VERSION 5.7 ;
  NOWIREEXTENSIONATPIN ON ;
  DIVIDERCHAR "/" ;
  BUSBITCHARS "[]" ;
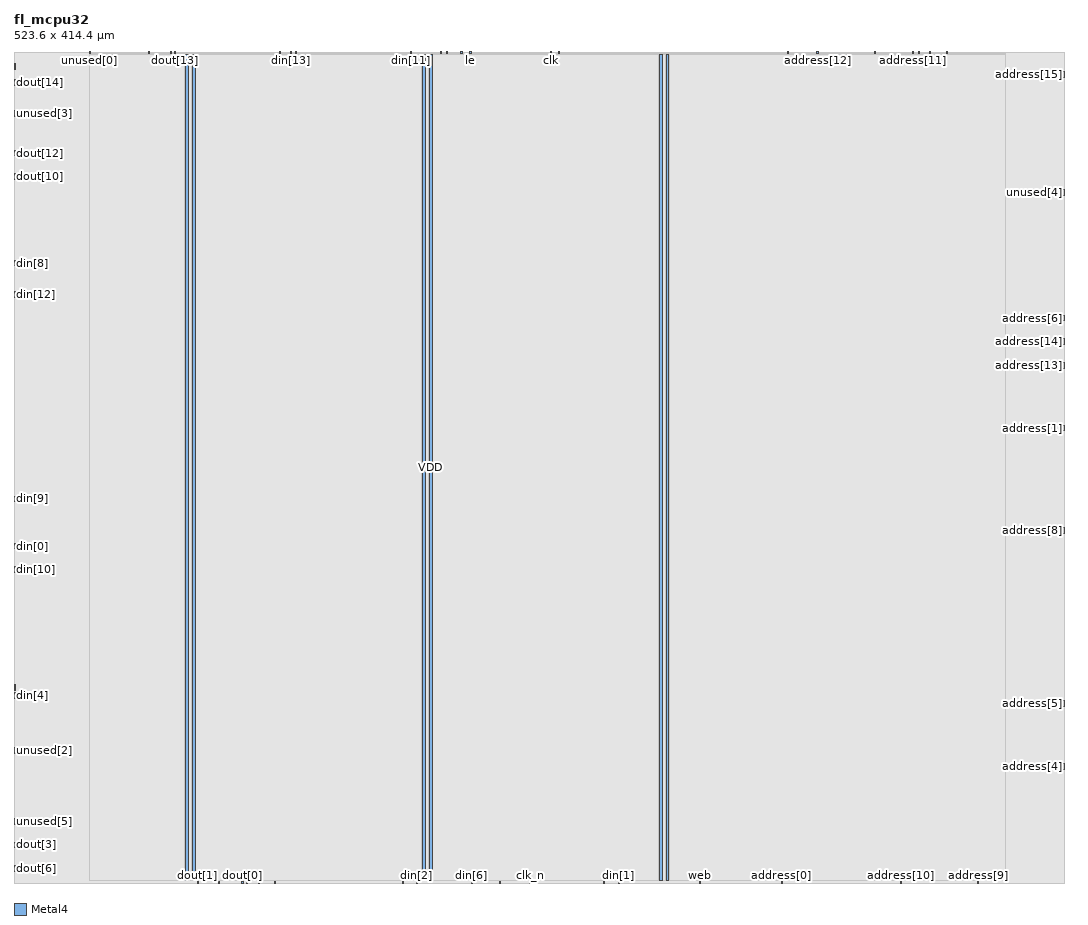
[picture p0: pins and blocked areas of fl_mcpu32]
MACRO fl_mcpu32
  CLASS BLOCK ;
  FOREIGN fl_mcpu32 ;
  ORIGIN 0.000 0.000 ;
  SIZE 523.600 BY 414.400 ;
  PIN VSS
    DIRECTION INOUT ;
    USE GROUND ;
    PORT
      LAYER Metal4 ;
        RECT 85.540 1.400 86.940 413.000 ;
    END
    PORT
      LAYER Metal4 ;
        RECT 203.700 1.400 205.100 413.000 ;
    END
    PORT
      LAYER Metal4 ;
        RECT 321.860 1.400 323.260 413.000 ;
    END
  END VSS
  PIN VDD
    DIRECTION INOUT ;
    USE POWER ;
    PORT
      LAYER Metal4 ;
        RECT 88.900 1.400 90.300 413.000 ;
    END
    PORT
      LAYER Metal4 ;
        RECT 207.060 1.400 208.460 413.000 ;
    END
    PORT
      LAYER Metal4 ;
        RECT 325.220 1.400 326.620 413.000 ;
    END
  END VDD
  PIN le
    DIRECTION OUTPUT ;
    USE SIGNAL ;
    ANTENNADIFFAREA 8.338300 ;
    PORT
      LAYER Metal4 ;
        RECT 227.360 413.840 227.920 414.400 ;
    END
  END le
  PIN clk
    DIRECTION INPUT ;
    USE SIGNAL ;
    ANTENNAGATEAREA 2.352000 ;
    ANTENNADIFFAREA 0.877000 ;
    PORT
      LAYER Metal4 ;
        RECT 267.680 413.840 268.240 414.400 ;
    END
  END clk
  PIN rst_n
    DIRECTION INPUT ;
    USE SIGNAL ;
    ANTENNAGATEAREA 1.999200 ;
    ANTENNADIFFAREA 0.877000 ;
    PORT
      LAYER Metal4 ;
        RECT 212.800 413.840 213.360 414.400 ;
    END
  END rst_n
  PIN rst_override_n
    DIRECTION INPUT ;
    USE SIGNAL ;
    ANTENNAGATEAREA 1.999200 ;
    ANTENNADIFFAREA 0.877000 ;
    PORT
      LAYER Metal4 ;
        RECT 77.840 413.840 78.400 414.400 ;
    END
  END rst_override_n
  PIN din[0]
    DIRECTION INPUT ;
    USE SIGNAL ;
    ANTENNAGATEAREA 1.999200 ;
    ANTENNADIFFAREA 0.877000 ;
    PORT
      LAYER Metal4 ;
        RECT 0.000 166.600 0.560 169.400 ;
    END
  END din[0]
  PIN clk_n
    DIRECTION INPUT ;
    USE SIGNAL ;
    ANTENNAGATEAREA 2.352000 ;
    ANTENNADIFFAREA 0.877000 ;
    PORT
      LAYER Metal4 ;
        RECT 257.040 0.000 257.600 0.560 ;
    END
  END clk_n
  PIN din[11]
    DIRECTION INPUT ;
    USE SIGNAL ;
    ANTENNAGATEAREA 1.999200 ;
    ANTENNADIFFAREA 0.877000 ;
    PORT
      LAYER Metal4 ;
        RECT 197.680 413.840 198.240 414.400 ;
    END
  END din[11]
  PIN din[10]
    DIRECTION INPUT ;
    USE SIGNAL ;
    ANTENNAGATEAREA 1.999200 ;
    ANTENNADIFFAREA 0.877000 ;
    PORT
      LAYER Metal4 ;
        RECT 0.000 154.840 0.560 157.640 ;
    END
  END din[10]
  PIN din[9]
    DIRECTION INPUT ;
    USE SIGNAL ;
    ANTENNAGATEAREA 1.999200 ;
    ANTENNADIFFAREA 0.877000 ;
    PORT
      LAYER Metal4 ;
        RECT 0.000 190.120 0.560 192.920 ;
    END
  END din[9]
  PIN din[8]
    DIRECTION INPUT ;
    USE SIGNAL ;
    ANTENNAGATEAREA 1.999200 ;
    ANTENNADIFFAREA 0.877000 ;
    PORT
      LAYER Metal4 ;
        RECT 0.000 307.720 0.560 310.520 ;
    END
  END din[8]
  PIN din[7]
    DIRECTION INPUT ;
    USE SIGNAL ;
    ANTENNAGATEAREA 1.999200 ;
    ANTENNADIFFAREA 0.877000 ;
    PORT
      LAYER Metal4 ;
        RECT 122.080 0.000 122.640 0.560 ;
    END
  END din[7]
  PIN din[6]
    DIRECTION INPUT ;
    USE SIGNAL ;
    ANTENNAGATEAREA 1.999200 ;
    ANTENNADIFFAREA 0.877000 ;
    PORT
      LAYER Metal4 ;
        RECT 227.920 0.000 228.480 0.560 ;
    END
  END din[6]
  PIN din[5]
    DIRECTION INPUT ;
    USE SIGNAL ;
    ANTENNAGATEAREA 1.999200 ;
    ANTENNADIFFAREA 0.877000 ;
    PORT
      LAYER Metal4 ;
        RECT 129.920 0.000 130.480 0.560 ;
    END
  END din[5]
  PIN din[4]
    DIRECTION INPUT ;
    USE SIGNAL ;
    ANTENNAGATEAREA 1.999200 ;
    ANTENNADIFFAREA 0.877000 ;
    PORT
      LAYER Metal4 ;
        RECT 0.000 92.120 0.560 94.920 ;
    END
  END din[4]
  PIN din[3]
    DIRECTION INPUT ;
    USE SIGNAL ;
    ANTENNAGATEAREA 1.999200 ;
    ANTENNADIFFAREA 0.877000 ;
    PORT
      LAYER Metal4 ;
        RECT 193.760 0.000 194.320 0.560 ;
    END
  END din[3]
  PIN din[2]
    DIRECTION INPUT ;
    USE SIGNAL ;
    ANTENNAGATEAREA 1.999200 ;
    ANTENNADIFFAREA 0.877000 ;
    PORT
      LAYER Metal4 ;
        RECT 200.480 0.000 201.040 0.560 ;
    END
  END din[2]
  PIN din[1]
    DIRECTION INPUT ;
    USE SIGNAL ;
    ANTENNAGATEAREA 1.999200 ;
    ANTENNADIFFAREA 0.877000 ;
    PORT
      LAYER Metal4 ;
        RECT 301.280 0.000 301.840 0.560 ;
    END
  END din[1]
  PIN din[12]
    DIRECTION INPUT ;
    USE SIGNAL ;
    ANTENNAGATEAREA 1.999200 ;
    ANTENNADIFFAREA 0.877000 ;
    PORT
      LAYER Metal4 ;
        RECT 0.000 292.040 0.560 294.840 ;
    END
  END din[12]
  PIN din[13]
    DIRECTION INPUT ;
    USE SIGNAL ;
    ANTENNAGATEAREA 1.999200 ;
    ANTENNADIFFAREA 0.877000 ;
    PORT
      LAYER Metal4 ;
        RECT 137.760 413.840 138.320 414.400 ;
    END
  END din[13]
  PIN din[15]
    DIRECTION INPUT ;
    USE SIGNAL ;
    ANTENNAGATEAREA 1.999200 ;
    ANTENNADIFFAREA 0.877000 ;
    PORT
      LAYER Metal4 ;
        RECT 241.920 0.000 242.480 0.560 ;
    END
  END din[15]
  PIN din[14]
    DIRECTION INPUT ;
    USE SIGNAL ;
    ANTENNAGATEAREA 1.999200 ;
    ANTENNADIFFAREA 0.877000 ;
    PORT
      LAYER Metal4 ;
        RECT 140.560 413.840 141.120 414.400 ;
    END
  END din[14]
  PIN address[0]
    DIRECTION OUTPUT ;
    USE SIGNAL ;
    ANTENNADIFFAREA 8.338300 ;
    PORT
      LAYER Metal4 ;
        RECT 382.480 0.000 383.040 0.560 ;
    END
  END address[0]
  PIN address[1]
    DIRECTION OUTPUT ;
    USE SIGNAL ;
    ANTENNADIFFAREA 8.338300 ;
    PORT
      LAYER Metal4 ;
        RECT 523.040 225.400 523.600 228.200 ;
    END
  END address[1]
  PIN address[11]
    DIRECTION OUTPUT ;
    USE SIGNAL ;
    ANTENNADIFFAREA 8.338300 ;
    PORT
      LAYER Metal4 ;
        RECT 448.000 413.840 448.560 414.400 ;
    END
  END address[11]
  PIN address[7]
    DIRECTION OUTPUT ;
    USE SIGNAL ;
    ANTENNADIFFAREA 8.338300 ;
    PORT
      LAYER Metal4 ;
        RECT 456.400 413.840 456.960 414.400 ;
    END
  END address[7]
  PIN address[8]
    DIRECTION OUTPUT ;
    USE SIGNAL ;
    ANTENNADIFFAREA 8.338300 ;
    PORT
      LAYER Metal4 ;
        RECT 523.040 174.440 523.600 177.240 ;
    END
  END address[8]
  PIN address[6]
    DIRECTION OUTPUT ;
    USE SIGNAL ;
    ANTENNADIFFAREA 8.338300 ;
    PORT
      LAYER Metal4 ;
        RECT 523.040 280.280 523.600 283.080 ;
    END
  END address[6]
  PIN address[4]
    DIRECTION OUTPUT ;
    USE SIGNAL ;
    ANTENNADIFFAREA 8.338300 ;
    PORT
      LAYER Metal4 ;
        RECT 523.040 56.840 523.600 59.640 ;
    END
  END address[4]
  PIN address[3]
    DIRECTION OUTPUT ;
    USE SIGNAL ;
    ANTENNADIFFAREA 8.338300 ;
    PORT
      LAYER Metal4 ;
        RECT 464.800 413.840 465.360 414.400 ;
    END
  END address[3]
  PIN address[13]
    DIRECTION OUTPUT ;
    USE SIGNAL ;
    ANTENNADIFFAREA 8.338300 ;
    PORT
      LAYER Metal4 ;
        RECT 523.040 256.760 523.600 259.560 ;
    END
  END address[13]
  PIN address[14]
    DIRECTION OUTPUT ;
    USE SIGNAL ;
    ANTENNADIFFAREA 8.338300 ;
    PORT
      LAYER Metal4 ;
        RECT 523.040 268.520 523.600 271.320 ;
    END
  END address[14]
  PIN address[12]
    DIRECTION OUTPUT ;
    USE SIGNAL ;
    ANTENNADIFFAREA 8.338300 ;
    PORT
      LAYER Metal4 ;
        RECT 400.400 413.840 400.960 414.400 ;
    END
  END address[12]
  PIN address[9]
    DIRECTION OUTPUT ;
    USE SIGNAL ;
    ANTENNADIFFAREA 8.338300 ;
    PORT
      LAYER Metal4 ;
        RECT 480.480 0.000 481.040 0.560 ;
    END
  END address[9]
  PIN address[2]
    DIRECTION OUTPUT ;
    USE SIGNAL ;
    ANTENNADIFFAREA 8.338300 ;
    PORT
      LAYER Metal4 ;
        RECT 450.800 413.840 451.360 414.400 ;
    END
  END address[2]
  PIN address[15]
    DIRECTION OUTPUT ;
    USE SIGNAL ;
    ANTENNADIFFAREA 8.338300 ;
    PORT
      LAYER Metal4 ;
        RECT 523.040 401.800 523.600 404.600 ;
    END
  END address[15]
  PIN address[10]
    DIRECTION OUTPUT ;
    USE SIGNAL ;
    ANTENNADIFFAREA 8.338300 ;
    PORT
      LAYER Metal4 ;
        RECT 441.840 0.000 442.400 0.560 ;
    END
  END address[10]
  PIN address[5]
    DIRECTION OUTPUT ;
    USE SIGNAL ;
    ANTENNADIFFAREA 8.338300 ;
    PORT
      LAYER Metal4 ;
        RECT 523.040 88.200 523.600 91.000 ;
    END
  END address[5]
  PIN dout[1]
    DIRECTION OUTPUT ;
    USE SIGNAL ;
    ANTENNADIFFAREA 8.338300 ;
    PORT
      LAYER Metal4 ;
        RECT 91.280 0.000 91.840 0.560 ;
    END
  END dout[1]
  PIN dout[2]
    DIRECTION OUTPUT ;
    USE SIGNAL ;
    ANTENNADIFFAREA 8.338300 ;
    PORT
      LAYER Metal4 ;
        RECT 294.000 0.000 294.560 0.560 ;
    END
  END dout[2]
  PIN dout[3]
    DIRECTION OUTPUT ;
    USE SIGNAL ;
    ANTENNADIFFAREA 8.338300 ;
    PORT
      LAYER Metal4 ;
        RECT 0.000 17.640 0.560 20.440 ;
    END
  END dout[3]
  PIN dout[4]
    DIRECTION OUTPUT ;
    USE SIGNAL ;
    ANTENNADIFFAREA 8.338300 ;
    PORT
      LAYER Metal4 ;
        RECT 215.600 413.840 216.160 414.400 ;
    END
  END dout[4]
  PIN dout[5]
    DIRECTION OUTPUT ;
    USE SIGNAL ;
    ANTENNADIFFAREA 8.338300 ;
    PORT
      LAYER Metal4 ;
        RECT 222.880 413.840 223.440 414.400 ;
    END
  END dout[5]
  PIN dout[6]
    DIRECTION OUTPUT ;
    USE SIGNAL ;
    ANTENNADIFFAREA 8.338300 ;
    PORT
      LAYER Metal4 ;
        RECT 0.000 5.880 0.560 8.680 ;
    END
  END dout[6]
  PIN dout[7]
    DIRECTION OUTPUT ;
    USE SIGNAL ;
    ANTENNADIFFAREA 8.338300 ;
    PORT
      LAYER Metal4 ;
        RECT 115.920 0.000 116.480 0.560 ;
    END
  END dout[7]
  PIN dout[15]
    DIRECTION OUTPUT ;
    USE SIGNAL ;
    ANTENNADIFFAREA 8.338300 ;
    PORT
      LAYER Metal4 ;
        RECT 0.000 405.720 0.560 408.520 ;
    END
  END dout[15]
  PIN dout[14]
    DIRECTION OUTPUT ;
    USE SIGNAL ;
    ANTENNADIFFAREA 8.338300 ;
    PORT
      LAYER Metal4 ;
        RECT 0.000 397.880 0.560 400.680 ;
    END
  END dout[14]
  PIN dout[13]
    DIRECTION OUTPUT ;
    USE SIGNAL ;
    ANTENNADIFFAREA 8.338300 ;
    PORT
      LAYER Metal4 ;
        RECT 80.080 413.840 80.640 414.400 ;
    END
  END dout[13]
  PIN dout[12]
    DIRECTION OUTPUT ;
    USE SIGNAL ;
    ANTENNADIFFAREA 8.338300 ;
    PORT
      LAYER Metal4 ;
        RECT 0.000 362.600 0.560 365.400 ;
    END
  END dout[12]
  PIN dout[11]
    DIRECTION OUTPUT ;
    USE SIGNAL ;
    ANTENNADIFFAREA 8.338300 ;
    PORT
      LAYER Metal4 ;
        RECT 101.920 0.000 102.480 0.560 ;
    END
  END dout[11]
  PIN dout[10]
    DIRECTION OUTPUT ;
    USE SIGNAL ;
    ANTENNADIFFAREA 8.338300 ;
    PORT
      LAYER Metal4 ;
        RECT 0.000 350.840 0.560 353.640 ;
    END
  END dout[10]
  PIN dout[9]
    DIRECTION OUTPUT ;
    USE SIGNAL ;
    ANTENNADIFFAREA 8.338300 ;
    PORT
      LAYER Metal4 ;
        RECT 132.160 413.840 132.720 414.400 ;
    END
  END dout[9]
  PIN dout[8]
    DIRECTION OUTPUT ;
    USE SIGNAL ;
    ANTENNADIFFAREA 8.338300 ;
    PORT
      LAYER Metal4 ;
        RECT 67.200 413.840 67.760 414.400 ;
    END
  END dout[8]
  PIN dout[0]
    DIRECTION OUTPUT ;
    USE SIGNAL ;
    ANTENNADIFFAREA 8.338300 ;
    PORT
      LAYER Metal4 ;
        RECT 113.680 0.000 114.240 0.560 ;
    END
  END dout[0]
  PIN oeb
    DIRECTION OUTPUT ;
    USE SIGNAL ;
    ANTENNADIFFAREA 8.338300 ;
    PORT
      LAYER Metal4 ;
        RECT 271.600 413.840 272.160 414.400 ;
    END
  END oeb
  PIN bus_enable
    DIRECTION OUTPUT ;
    USE SIGNAL ;
    ANTENNADIFFAREA 8.338300 ;
    PORT
      LAYER Metal4 ;
        RECT 385.840 413.840 386.400 414.400 ;
    END
  END bus_enable
  PIN web
    DIRECTION OUTPUT ;
    USE SIGNAL ;
    ANTENNADIFFAREA 8.338300 ;
    PORT
      LAYER Metal4 ;
        RECT 341.600 0.000 342.160 0.560 ;
    END
  END web
  PIN unused[0]
    DIRECTION OUTPUT ;
    USE SIGNAL ;
    ANTENNADIFFAREA 8.338300 ;
    PORT
      LAYER Metal4 ;
        RECT 37.520 413.840 38.080 414.400 ;
    END
  END unused[0]
  PIN unused[1]
    DIRECTION OUTPUT ;
    USE SIGNAL ;
    ANTENNADIFFAREA 8.338300 ;
    PORT
      LAYER Metal4 ;
        RECT 428.960 413.840 429.520 414.400 ;
    END
  END unused[1]
  PIN unused[2]
    DIRECTION OUTPUT ;
    USE SIGNAL ;
    ANTENNADIFFAREA 8.338300 ;
    PORT
      LAYER Metal4 ;
        RECT 0.000 64.680 0.560 67.480 ;
    END
  END unused[2]
  PIN unused[3]
    DIRECTION OUTPUT ;
    USE SIGNAL ;
    ANTENNADIFFAREA 8.338300 ;
    PORT
      LAYER Metal4 ;
        RECT 0.000 382.200 0.560 385.000 ;
    END
  END unused[3]
  PIN unused[4]
    DIRECTION OUTPUT ;
    USE SIGNAL ;
    ANTENNADIFFAREA 8.338300 ;
    PORT
      LAYER Metal4 ;
        RECT 523.040 343.000 523.600 345.800 ;
    END
  END unused[4]
  PIN unused[5]
    DIRECTION OUTPUT ;
    USE SIGNAL ;
    ANTENNADIFFAREA 8.338300 ;
    PORT
      LAYER Metal4 ;
        RECT 0.000 29.400 0.560 32.200 ;
    END
  END unused[5]
  PIN unused[6]
    DIRECTION OUTPUT ;
    USE SIGNAL ;
    ANTENNADIFFAREA 8.338300 ;
    PORT
      LAYER Metal4 ;
        RECT 0.000 96.040 0.560 98.840 ;
    END
  END unused[6]
  OBS
      LAYER Nwell ;
        RECT 0.970 0.970 522.630 413.430 ;
      LAYER Metal1 ;
        RECT 1.400 1.100 522.200 413.300 ;
      LAYER Metal2 ;
        RECT 0.000 0.000 523.600 414.320 ;
      LAYER Metal3 ;
        RECT 0.000 0.000 523.600 414.320 ;
      LAYER Metal4 ;
        RECT 38.380 413.540 66.900 413.840 ;
        RECT 68.060 413.540 77.540 413.840 ;
        RECT 78.700 413.540 79.780 413.840 ;
        RECT 80.940 413.540 131.860 413.840 ;
        RECT 133.020 413.540 137.460 413.840 ;
        RECT 138.620 413.540 140.260 413.840 ;
        RECT 141.420 413.540 197.380 413.840 ;
        RECT 198.540 413.540 212.500 413.840 ;
        RECT 213.660 413.540 215.300 413.840 ;
        RECT 216.460 413.540 222.580 413.840 ;
        RECT 223.740 413.540 227.060 413.840 ;
        RECT 228.220 413.540 267.380 413.840 ;
        RECT 268.540 413.540 271.300 413.840 ;
        RECT 272.460 413.540 385.540 413.840 ;
        RECT 386.700 413.540 400.100 413.840 ;
        RECT 401.260 413.540 428.660 413.840 ;
        RECT 429.820 413.540 447.700 413.840 ;
        RECT 448.860 413.540 450.500 413.840 ;
        RECT 451.660 413.540 456.100 413.840 ;
        RECT 457.260 413.540 464.500 413.840 ;
        RECT 465.660 413.540 494.620 413.840 ;
        RECT 37.520 413.300 494.620 413.540 ;
        RECT 37.520 1.120 85.240 413.300 ;
        RECT 87.240 1.120 88.600 413.300 ;
        RECT 90.600 1.120 203.400 413.300 ;
        RECT 205.400 1.120 206.760 413.300 ;
        RECT 208.760 1.120 321.560 413.300 ;
        RECT 323.560 1.120 324.920 413.300 ;
        RECT 326.920 1.120 494.620 413.300 ;
  END
END fl_mcpu32
END LIBRARY

